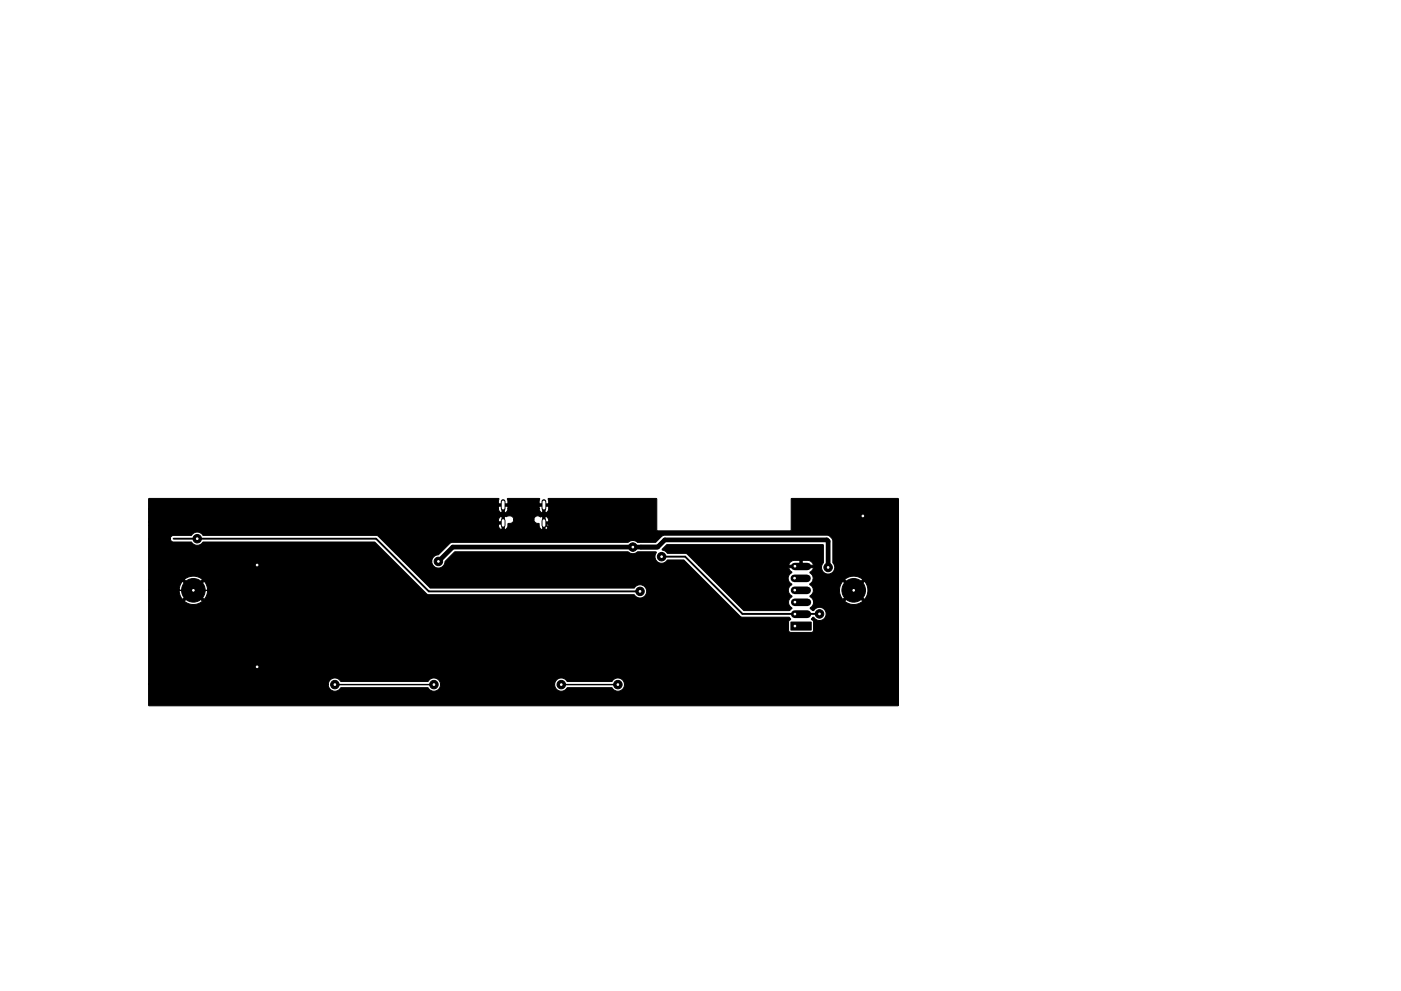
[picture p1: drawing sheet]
<svg xmlns="http://www.w3.org/2000/svg" width="297mm" height="210mm" viewBox="0 0 297 210" stroke-linecap="round" stroke-linejoin="round" font-family="sans-serif">
<g fill="#000" stroke="#000" stroke-width=".21">
<path d="M31.5 105.8l74.2-.1 .1 .2-.1 1h2l-.1-1 .1-.2h6.6l.1 .2-.1 1h2l-.1-1 .1-.2h22.8l.1 .2v6.7h28.5l.1-6.8h22.7l-.1 43.9h-158.8l-.1-.1v-4.4h38.1a1.45 1.45 0 0 0 1.1 1.4 1.45 1.45 0 0 0 1.6-.7h18.5a1.41 1.41 0 0 0 1.6 .7 1.41 1.41 0 0 0 1-1.4h24.2a1.45 1.45 0 0 0 1.1 1.4 1.45 1.45 0 0 0 1.6-.7h9.5a1.43 1.43 0 0 0 2.1 .3 1.43 1.43 0 0 0-.1-2.2 1.43 1.43 0 0 0-2.1 .6h-9.4l-.3-.4a1.41 1.41 0 0 0-1.5-.2 1.41 1.41 0 0 0-.9 1.2h-24.2v-.2a1.45 1.45 0 0 0-1.2-1.1 1.45 1.45 0 0 0-1.5 .7h-18.4l-.3-.4a1.41 1.41 0 0 0-1.5-.2 1.41 1.41 0 0 0-.9 1.2h-38.1v-17.6h7.6a2.96 2.96 0 0 0 3.8-.1l-1.9-1.9-1.9 2h-7.6v-2.4h6.5l.1 1 .6 1 1.9-2h.8l1.9 2a2.96 2.96 0 0 0 0-3.9l-1.9 1.9h-.8l-1.9-1.9-.5 .8-.2 1.1h-6.5v-2.3h7.6l1.9 2 1.9-1.9a2.95 2.95 0 0 0-3.8-.1h-7.6v-8.5h4.6l.1 .3 .4 .3h3.9a1.52 1.52 0 0 0 2.6 0h36.3l11 11 .5 .2h43.6a1.43 1.43 0 0 0 2.2 .3 1.43 1.43 0 0 0-.2-2.2 1.43 1.43 0 0 0-2.1 .5h-43.1l-5.8-5.7h6a1.42 1.42 0 0 0 1.5 1.4 1.42 1.42 0 0 0 1.4-1.4l2.1-2h36.6a1.52 1.52 0 0 0 2.1 0h3.8l.2 .1a1.44 1.44 0 0 0 .3 2.1 1.44 1.44 0 0 0 2.1-.5h3.4l12.2 12.1 10.1 .1 .3 .3-.4 .6v1.8l.1 .3 .3 .2 4.6-.1 .3-.3v-1.9l-.5-.5 .4-.5a1.53 1.53 0 0 0 2.6 .1 1.43 1.43 0 0 0-.6-2 1.43 1.43 0 0 0-1.9 .5h-.3l-.4-.5 .5-.6 .2-.8h6.6a2.96 2.96 0 0 0 3.8-.1l-1.9-1.9-1.9 2h-6.6l-.3-.7-.5-.4a1.59 1.59 0 0 0 .7-1.3h5.6l.1 1 .6 1 1.9-2h.8l1.9 2a2.96 2.96 0 0 0 0-3.9l-1.9 1.9h-.8l-1.9-1.9-.5 .8-.2 1.1h-5.6l-.1-.6-.6-.6 .4-.4 .3-.7h6.7l1.9 2 1.9-1.9a2.95 2.95 0 0 0-3.8-.1h-6.7a1.32 1.32 0 0 0-.6-1.3l-.1-.2 .5-.4 .3-.6h-5.3l.3 .6 .4 .4a1.68 1.68 0 0 0-.6 2l.6 .6a1.44 1.44 0 0 0 0 2.5 1.38 1.38 0 0 0 0 2.4v.2l-.5 .4h-9.7l-9.6-9.6h24.4a1.25 1.25 0 0 0-1.2-1h-1.2v1h-.5v-1h-1.2l-.8 .3-.4 .7h-19.1l-2.5-2.4-4-.1-1.2-.8 1-1.1h33.1l.1 .2v3.7l-.3 .4a1.41 1.41 0 0 0 1.6 2 1.41 1.41 0 0 0 .7-2.4v-4.8l-.6-.8-.6-.3h-34.5l-.6 .3-1.3 1.3-3.9-.1a1.46 1.46 0 0 0-2 .1h-37.2l-.5 .2-2.5 2.4a1.4 1.4 0 0 0-1.4 1.4h-6l-5.3-5.3-.4-.2h-36.7l-.3-.3a1.47 1.47 0 0 0-2.3 .3h-3.9l-.4 .3-.1 .5h-4.6v-2.9h74.2l.4 .8 .8 .1 .6-.4 .2-.9 .9-.2 .3-.7h4.3a.94 .94 0 0 0 1.1 .9v.4a.96 .96 0 0 0 .8 .9h.5a.95 .95 0 0 0 .7-.9v-.3h-.7v1.2h-.5v-1.7h1.2v-.3a.96 .96 0 0 0-.7-.9v1.2h-.5v-1.2l-.6 .1a.81 .81 0 0 0-1 0l-.3 .6h-4.3l-.1-.4-.3-.3-.7-.1-.5 .2-.4-.1v2.9h-.5v-1.2h-.7v.3h-74.2v-.8h74.9v-1.2a.94 .94 0 0 0-.7 .9v.3h-74.2v-2.8h74.2a.96 .96 0 0 0 .7 1h.5a.94 .94 0 0 0 .8-1h6.6l.4 .8 .9 .2 .6-.6 .1-.9h-.7v1.5h-.5v-1.5h-.8v.5h-6.6v-.5h-.7l-.1 1.5h-.5v-1.5h-.7v.5h-74.2zM167.7 132h4.3v1.7h-4.3z"/>
<circle cx="41.8" cy="114.3" r=".9"/>
<circle cx="54.5" cy="119.9" r=".9"/>
<circle cx="92.9" cy="119.1" r=".9"/>
<circle cx="134.2" cy="116.1" r=".9"/>
<circle cx="140.3" cy="118.1" r=".9"/>
<circle cx="182.9" cy="109.5" r=".9"/>
<circle cx="41" cy="125.2" r="2.5"/>
<circle cx="135.7" cy="125.5" r=".9"/>
<circle cx="173.8" cy="130.2" r=".9"/>
<circle cx="175.6" cy="120.4" r=".9"/>
<circle cx="181" cy="125.2" r="2.5"/>
<circle cx="54.5" cy="141.5" r=".9"/>
<circle cx="71" cy="145.2" r=".9"/>
<circle cx="92" cy="145.2" r=".9"/>
<circle cx="119" cy="145.2" r=".9"/>
<circle cx="131" cy="145.2" r=".9"/>
</g>
<path d="M168.5 130.3h2.7" fill="none" stroke="#000" stroke-width="1.7"/>
<path d="M168.4 122.7h2.7M168.5 125.2h2.6M168.5 120.2h2.7M168.5 127.8h2.7" fill="none" stroke="#000" stroke-width="1.6"/>
<path d="M92.9 119.1l3.1-3h43.4l1.6-1.6h34.3l.3 .3v5.6M106.7 106.4v1.5M106.7 110.4v1M115.3 106.4v1.5M115.3 110.5v1" fill="none" stroke="#000" stroke-width="1"/>
<path d="M49.5 119.9v21.6M49.5 125.2h-13.5M71 145.2h21M119 145.2h12" fill="none" stroke="#000" stroke-width=".3"/>
<path d="M36.8 114.3h42.9l11.2 11.2h44.8M106.7 107.1v3.8M140.3 118.1h5l12.1 12.1h16.4M186 111.4v13.8M187.9 109.5l-3.3 3.3h-67.4l-1.9-1.8" fill="none" stroke="#000" stroke-width=".4"/>
<g fill="#fff" stroke="#fff" stroke-width=".21">
<circle cx="119" cy="145.2" r=".17"/>
<circle cx="131" cy="145.2" r=".17"/>
<circle cx="92" cy="145.2" r=".17"/>
<circle cx="71" cy="145.2" r=".17"/>
<circle cx="182.9" cy="109.5" r=".17"/>
<circle cx="54.5" cy="119.9" r=".17"/>
<circle cx="54.5" cy="141.5" r=".17"/>
<circle cx="41.8" cy="114.3" r=".17"/>
<circle cx="135.7" cy="125.5" r=".17"/>
<circle cx="175.6" cy="120.4" r=".17"/>
<circle cx="140.3" cy="118.1" r=".17"/>
<circle cx="173.8" cy="130.2" r=".17"/>
<circle cx="134.2" cy="116.1" r=".17"/>
<circle cx="92.9" cy="119.1" r=".17"/>
<circle cx="181" cy="125.2" r=".18"/>
<circle cx="168.5" cy="132.8" r=".17"/>
<circle cx="168.5" cy="130.3" r=".17"/>
<circle cx="168.5" cy="127.7" r=".17"/>
<circle cx="168.5" cy="125.2" r=".17"/>
<circle cx="168.5" cy="122.7" r=".17"/>
<circle cx="168.5" cy="120.1" r=".17"/>
<circle cx="41" cy="125.2" r=".17"/>
<circle cx="114" cy="110.2" r=".17"/>
</g>
<path d="M106.7 106.5v1.3M106.7 110.4v1M107.9 110.2h.2M115.3 106.5v1.3M115.3 110.5v1" fill="none" stroke="#fff" stroke-width=".6"/>
</svg>
